VERSION 5.7 ;
  NOWIREEXTENSIONATPIN ON ;
  DIVIDERCHAR "/" ;
  BUSBITCHARS "[]" ;
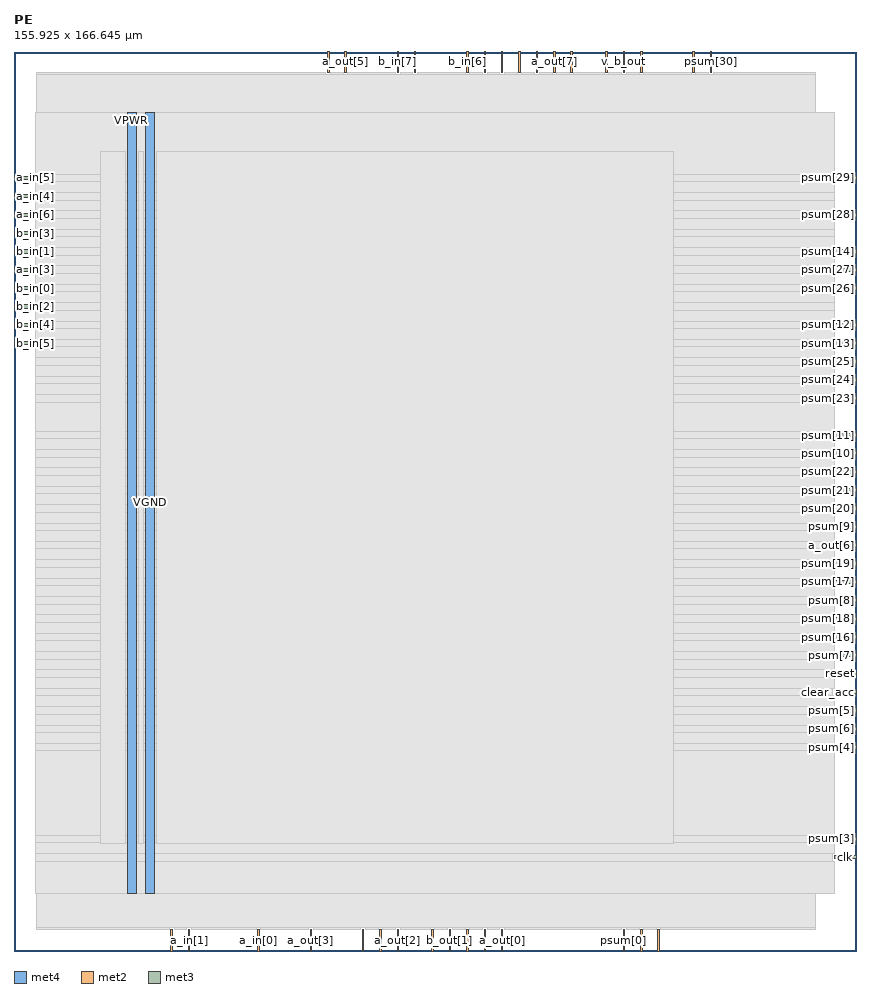
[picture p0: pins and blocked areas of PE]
MACRO PE
  CLASS BLOCK ;
  FOREIGN PE ;
  ORIGIN 0.000 0.000 ;
  SIZE 155.925 BY 166.645 ;
  PIN VGND
    DIRECTION INOUT ;
    USE GROUND ;
    PORT
      LAYER met4 ;
        RECT 24.340 10.640 25.940 155.280 ;
    END
  END VGND
  PIN VPWR
    DIRECTION INOUT ;
    USE POWER ;
    PORT
      LAYER met4 ;
        RECT 21.040 10.640 22.640 155.280 ;
    END
  END VPWR
  PIN a_in[0]
    DIRECTION INPUT ;
    USE SIGNAL ;
    ANTENNAGATEAREA 0.196500 ;
    PORT
      LAYER met2 ;
        RECT 45.170 0.000 45.450 4.000 ;
    END
  END a_in[0]
  PIN a_in[1]
    DIRECTION INPUT ;
    USE SIGNAL ;
    ANTENNAGATEAREA 0.213000 ;
    PORT
      LAYER met2 ;
        RECT 32.290 0.000 32.570 4.000 ;
    END
  END a_in[1]
  PIN a_in[2]
    DIRECTION INPUT ;
    USE SIGNAL ;
    ANTENNAGATEAREA 0.196500 ;
    PORT
      LAYER met2 ;
        RECT 29.070 0.000 29.350 4.000 ;
    END
  END a_in[2]
  PIN a_in[3]
    DIRECTION INPUT ;
    USE SIGNAL ;
    ANTENNAGATEAREA 0.196500 ;
    PORT
      LAYER met3 ;
        RECT 0.000 125.840 4.000 126.440 ;
    END
  END a_in[3]
  PIN a_in[4]
    DIRECTION INPUT ;
    USE SIGNAL ;
    ANTENNAGATEAREA 0.159000 ;
    PORT
      LAYER met3 ;
        RECT 0.000 139.440 4.000 140.040 ;
    END
  END a_in[4]
  PIN a_in[5]
    DIRECTION INPUT ;
    USE SIGNAL ;
    ANTENNAGATEAREA 0.196500 ;
    PORT
      LAYER met3 ;
        RECT 0.000 142.840 4.000 143.440 ;
    END
  END a_in[5]
  PIN a_in[6]
    DIRECTION INPUT ;
    USE SIGNAL ;
    ANTENNAGATEAREA 0.495000 ;
    PORT
      LAYER met3 ;
        RECT 0.000 136.040 4.000 136.640 ;
    END
  END a_in[6]
  PIN a_in[7]
    DIRECTION INPUT ;
    USE SIGNAL ;
    ANTENNAGATEAREA 0.196500 ;
    PORT
      LAYER met2 ;
        RECT 74.150 162.645 74.430 166.645 ;
    END
  END a_in[7]
  PIN a_out[0]
    DIRECTION OUTPUT ;
    USE SIGNAL ;
    ANTENNADIFFAREA 0.445500 ;
    PORT
      LAYER met2 ;
        RECT 90.250 0.000 90.530 4.000 ;
    END
  END a_out[0]
  PIN a_out[1]
    DIRECTION OUTPUT ;
    USE SIGNAL ;
    ANTENNADIFFAREA 0.445500 ;
    PORT
      LAYER met2 ;
        RECT 83.810 0.000 84.090 4.000 ;
    END
  END a_out[1]
  PIN a_out[2]
    DIRECTION OUTPUT ;
    USE SIGNAL ;
    ANTENNADIFFAREA 0.445500 ;
    PORT
      LAYER met2 ;
        RECT 70.930 0.000 71.210 4.000 ;
    END
  END a_out[2]
  PIN a_out[3]
    DIRECTION OUTPUT ;
    USE SIGNAL ;
    ANTENNADIFFAREA 0.445500 ;
    PORT
      LAYER met2 ;
        RECT 54.830 0.000 55.110 4.000 ;
    END
  END a_out[3]
  PIN a_out[4]
    DIRECTION OUTPUT ;
    USE SIGNAL ;
    ANTENNADIFFAREA 0.445500 ;
    PORT
      LAYER met2 ;
        RECT 58.050 162.645 58.330 166.645 ;
    END
  END a_out[4]
  PIN a_out[5]
    DIRECTION OUTPUT ;
    USE SIGNAL ;
    ANTENNADIFFAREA 0.445500 ;
    PORT
      LAYER met2 ;
        RECT 61.270 162.645 61.550 166.645 ;
    END
  END a_out[5]
  PIN a_out[6]
    DIRECTION OUTPUT ;
    USE SIGNAL ;
    ANTENNADIFFAREA 0.445500 ;
    PORT
      LAYER met3 ;
        RECT 151.925 74.840 155.925 75.440 ;
    END
  END a_out[6]
  PIN a_out[7]
    DIRECTION OUTPUT ;
    USE SIGNAL ;
    ANTENNADIFFAREA 0.445500 ;
    PORT
      LAYER met2 ;
        RECT 99.910 162.645 100.190 166.645 ;
    END
  END a_out[7]
  PIN b_in[0]
    DIRECTION INPUT ;
    USE SIGNAL ;
    ANTENNAGATEAREA 0.196500 ;
    PORT
      LAYER met3 ;
        RECT 0.000 122.440 4.000 123.040 ;
    END
  END b_in[0]
  PIN b_in[1]
    DIRECTION INPUT ;
    USE SIGNAL ;
    ANTENNAGATEAREA 0.742500 ;
    PORT
      LAYER met3 ;
        RECT 0.000 129.240 4.000 129.840 ;
    END
  END b_in[1]
  PIN b_in[2]
    DIRECTION INPUT ;
    USE SIGNAL ;
    ANTENNAGATEAREA 0.196500 ;
    PORT
      LAYER met3 ;
        RECT 0.000 119.040 4.000 119.640 ;
    END
  END b_in[2]
  PIN b_in[3]
    DIRECTION INPUT ;
    USE SIGNAL ;
    ANTENNAGATEAREA 0.196500 ;
    PORT
      LAYER met3 ;
        RECT 0.000 132.640 4.000 133.240 ;
    END
  END b_in[3]
  PIN b_in[4]
    DIRECTION INPUT ;
    USE SIGNAL ;
    ANTENNAGATEAREA 0.196500 ;
    PORT
      LAYER met3 ;
        RECT 0.000 115.640 4.000 116.240 ;
    END
  END b_in[4]
  PIN b_in[5]
    DIRECTION INPUT ;
    USE SIGNAL ;
    ANTENNAGATEAREA 0.196500 ;
    PORT
      LAYER met3 ;
        RECT 0.000 112.240 4.000 112.840 ;
    END
  END b_in[5]
  PIN b_in[6]
    DIRECTION INPUT ;
    USE SIGNAL ;
    ANTENNAGATEAREA 0.196500 ;
    PORT
      LAYER met2 ;
        RECT 83.810 162.645 84.090 166.645 ;
    END
  END b_in[6]
  PIN b_in[7]
    DIRECTION INPUT ;
    USE SIGNAL ;
    ANTENNAGATEAREA 0.196500 ;
    PORT
      LAYER met2 ;
        RECT 70.930 162.645 71.210 166.645 ;
    END
  END b_in[7]
  PIN b_out[0]
    DIRECTION OUTPUT ;
    USE SIGNAL ;
    ANTENNADIFFAREA 0.445500 ;
    PORT
      LAYER met2 ;
        RECT 87.030 0.000 87.310 4.000 ;
    END
  END b_out[0]
  PIN b_out[1]
    DIRECTION OUTPUT ;
    USE SIGNAL ;
    ANTENNADIFFAREA 0.445500 ;
    PORT
      LAYER met2 ;
        RECT 80.590 0.000 80.870 4.000 ;
    END
  END b_out[1]
  PIN b_out[2]
    DIRECTION OUTPUT ;
    USE SIGNAL ;
    ANTENNADIFFAREA 0.445500 ;
    PORT
      LAYER met2 ;
        RECT 77.370 0.000 77.650 4.000 ;
    END
  END b_out[2]
  PIN b_out[3]
    DIRECTION OUTPUT ;
    USE SIGNAL ;
    ANTENNADIFFAREA 0.445500 ;
    PORT
      LAYER met2 ;
        RECT 64.490 0.000 64.770 4.000 ;
    END
  END b_out[3]
  PIN b_out[4]
    DIRECTION OUTPUT ;
    USE SIGNAL ;
    ANTENNADIFFAREA 0.445500 ;
    PORT
      LAYER met2 ;
        RECT 67.710 0.000 67.990 4.000 ;
    END
  END b_out[4]
  PIN b_out[5]
    DIRECTION OUTPUT ;
    USE SIGNAL ;
    ANTENNADIFFAREA 0.445500 ;
    PORT
      LAYER met2 ;
        RECT 90.250 162.645 90.530 166.645 ;
    END
  END b_out[5]
  PIN b_out[6]
    DIRECTION OUTPUT ;
    USE SIGNAL ;
    ANTENNADIFFAREA 0.445500 ;
    PORT
      LAYER met2 ;
        RECT 87.030 162.645 87.310 166.645 ;
    END
  END b_out[6]
  PIN b_out[7]
    DIRECTION OUTPUT ;
    USE SIGNAL ;
    ANTENNADIFFAREA 0.445500 ;
    PORT
      LAYER met2 ;
        RECT 96.690 162.645 96.970 166.645 ;
    END
  END b_out[7]
  PIN clear_acc
    DIRECTION INPUT ;
    USE SIGNAL ;
    ANTENNAGATEAREA 0.126000 ;
    PORT
      LAYER met3 ;
        RECT 151.925 47.640 155.925 48.240 ;
    END
  END clear_acc
  PIN clk
    DIRECTION INPUT ;
    USE SIGNAL ;
    ANTENNAGATEAREA 0.852000 ;
    PORT
      LAYER met3 ;
        RECT 151.925 17.040 155.925 17.640 ;
    END
  END clk
  PIN psum[0]
    DIRECTION OUTPUT ;
    USE SIGNAL ;
    ANTENNADIFFAREA 0.445500 ;
    PORT
      LAYER met2 ;
        RECT 112.790 0.000 113.070 4.000 ;
    END
  END psum[0]
  PIN psum[10]
    DIRECTION OUTPUT ;
    USE SIGNAL ;
    ANTENNADIFFAREA 0.445500 ;
    PORT
      LAYER met3 ;
        RECT 151.925 91.840 155.925 92.440 ;
    END
  END psum[10]
  PIN psum[11]
    DIRECTION OUTPUT ;
    USE SIGNAL ;
    ANTENNADIFFAREA 0.445500 ;
    PORT
      LAYER met3 ;
        RECT 151.925 95.240 155.925 95.840 ;
    END
  END psum[11]
  PIN psum[12]
    DIRECTION OUTPUT ;
    USE SIGNAL ;
    ANTENNADIFFAREA 0.445500 ;
    PORT
      LAYER met3 ;
        RECT 151.925 115.640 155.925 116.240 ;
    END
  END psum[12]
  PIN psum[13]
    DIRECTION OUTPUT ;
    USE SIGNAL ;
    ANTENNADIFFAREA 0.445500 ;
    PORT
      LAYER met3 ;
        RECT 151.925 112.240 155.925 112.840 ;
    END
  END psum[13]
  PIN psum[14]
    DIRECTION OUTPUT ;
    USE SIGNAL ;
    ANTENNADIFFAREA 0.445500 ;
    PORT
      LAYER met3 ;
        RECT 151.925 129.240 155.925 129.840 ;
    END
  END psum[14]
  PIN psum[15]
    DIRECTION OUTPUT ;
    USE SIGNAL ;
    ANTENNADIFFAREA 0.445500 ;
    PORT
      LAYER met2 ;
        RECT 116.010 162.645 116.290 166.645 ;
    END
  END psum[15]
  PIN psum[16]
    DIRECTION OUTPUT ;
    USE SIGNAL ;
    ANTENNADIFFAREA 0.445500 ;
    PORT
      LAYER met3 ;
        RECT 151.925 57.840 155.925 58.440 ;
    END
  END psum[16]
  PIN psum[17]
    DIRECTION OUTPUT ;
    USE SIGNAL ;
    ANTENNADIFFAREA 0.445500 ;
    PORT
      LAYER met3 ;
        RECT 151.925 68.040 155.925 68.640 ;
    END
  END psum[17]
  PIN psum[18]
    DIRECTION OUTPUT ;
    USE SIGNAL ;
    ANTENNADIFFAREA 0.445500 ;
    PORT
      LAYER met3 ;
        RECT 151.925 61.240 155.925 61.840 ;
    END
  END psum[18]
  PIN psum[19]
    DIRECTION OUTPUT ;
    USE SIGNAL ;
    ANTENNADIFFAREA 0.445500 ;
    PORT
      LAYER met3 ;
        RECT 151.925 71.440 155.925 72.040 ;
    END
  END psum[19]
  PIN psum[1]
    DIRECTION OUTPUT ;
    USE SIGNAL ;
    ANTENNADIFFAREA 0.445500 ;
    PORT
      LAYER met2 ;
        RECT 116.010 0.000 116.290 4.000 ;
    END
  END psum[1]
  PIN psum[20]
    DIRECTION OUTPUT ;
    USE SIGNAL ;
    ANTENNADIFFAREA 0.445500 ;
    PORT
      LAYER met3 ;
        RECT 151.925 81.640 155.925 82.240 ;
    END
  END psum[20]
  PIN psum[21]
    DIRECTION OUTPUT ;
    USE SIGNAL ;
    ANTENNADIFFAREA 0.445500 ;
    PORT
      LAYER met3 ;
        RECT 151.925 85.040 155.925 85.640 ;
    END
  END psum[21]
  PIN psum[22]
    DIRECTION OUTPUT ;
    USE SIGNAL ;
    ANTENNADIFFAREA 0.445500 ;
    PORT
      LAYER met3 ;
        RECT 151.925 88.440 155.925 89.040 ;
    END
  END psum[22]
  PIN psum[23]
    DIRECTION OUTPUT ;
    USE SIGNAL ;
    ANTENNADIFFAREA 0.445500 ;
    PORT
      LAYER met3 ;
        RECT 151.925 102.040 155.925 102.640 ;
    END
  END psum[23]
  PIN psum[24]
    DIRECTION OUTPUT ;
    USE SIGNAL ;
    ANTENNADIFFAREA 0.445500 ;
    PORT
      LAYER met3 ;
        RECT 151.925 105.440 155.925 106.040 ;
    END
  END psum[24]
  PIN psum[25]
    DIRECTION OUTPUT ;
    USE SIGNAL ;
    ANTENNADIFFAREA 0.445500 ;
    PORT
      LAYER met3 ;
        RECT 151.925 108.840 155.925 109.440 ;
    END
  END psum[25]
  PIN psum[26]
    DIRECTION OUTPUT ;
    USE SIGNAL ;
    ANTENNADIFFAREA 0.445500 ;
    PORT
      LAYER met3 ;
        RECT 151.925 122.440 155.925 123.040 ;
    END
  END psum[26]
  PIN psum[27]
    DIRECTION OUTPUT ;
    USE SIGNAL ;
    ANTENNADIFFAREA 0.445500 ;
    PORT
      LAYER met3 ;
        RECT 151.925 125.840 155.925 126.440 ;
    END
  END psum[27]
  PIN psum[28]
    DIRECTION OUTPUT ;
    USE SIGNAL ;
    ANTENNADIFFAREA 0.445500 ;
    PORT
      LAYER met3 ;
        RECT 151.925 136.040 155.925 136.640 ;
    END
  END psum[28]
  PIN psum[29]
    DIRECTION OUTPUT ;
    USE SIGNAL ;
    ANTENNADIFFAREA 0.445500 ;
    PORT
      LAYER met3 ;
        RECT 151.925 142.840 155.925 143.440 ;
    END
  END psum[29]
  PIN psum[2]
    DIRECTION OUTPUT ;
    USE SIGNAL ;
    ANTENNADIFFAREA 0.445500 ;
    PORT
      LAYER met2 ;
        RECT 119.230 0.000 119.510 4.000 ;
    END
  END psum[2]
  PIN psum[30]
    DIRECTION OUTPUT ;
    USE SIGNAL ;
    ANTENNADIFFAREA 0.445500 ;
    PORT
      LAYER met2 ;
        RECT 128.890 162.645 129.170 166.645 ;
    END
  END psum[30]
  PIN psum[31]
    DIRECTION OUTPUT ;
    USE SIGNAL ;
    ANTENNADIFFAREA 0.445500 ;
    PORT
      LAYER met2 ;
        RECT 125.670 162.645 125.950 166.645 ;
    END
  END psum[31]
  PIN psum[3]
    DIRECTION OUTPUT ;
    USE SIGNAL ;
    ANTENNADIFFAREA 0.445500 ;
    PORT
      LAYER met3 ;
        RECT 151.925 20.440 155.925 21.040 ;
    END
  END psum[3]
  PIN psum[4]
    DIRECTION OUTPUT ;
    USE SIGNAL ;
    ANTENNADIFFAREA 0.445500 ;
    PORT
      LAYER met3 ;
        RECT 151.925 37.440 155.925 38.040 ;
    END
  END psum[4]
  PIN psum[5]
    DIRECTION OUTPUT ;
    USE SIGNAL ;
    ANTENNADIFFAREA 0.445500 ;
    PORT
      LAYER met3 ;
        RECT 151.925 44.240 155.925 44.840 ;
    END
  END psum[5]
  PIN psum[6]
    DIRECTION OUTPUT ;
    USE SIGNAL ;
    ANTENNADIFFAREA 0.445500 ;
    PORT
      LAYER met3 ;
        RECT 151.925 40.840 155.925 41.440 ;
    END
  END psum[6]
  PIN psum[7]
    DIRECTION OUTPUT ;
    USE SIGNAL ;
    ANTENNADIFFAREA 0.445500 ;
    PORT
      LAYER met3 ;
        RECT 151.925 54.440 155.925 55.040 ;
    END
  END psum[7]
  PIN psum[8]
    DIRECTION OUTPUT ;
    USE SIGNAL ;
    ANTENNADIFFAREA 0.445500 ;
    PORT
      LAYER met3 ;
        RECT 151.925 64.640 155.925 65.240 ;
    END
  END psum[8]
  PIN psum[9]
    DIRECTION OUTPUT ;
    USE SIGNAL ;
    ANTENNADIFFAREA 0.445500 ;
    PORT
      LAYER met3 ;
        RECT 151.925 78.240 155.925 78.840 ;
    END
  END psum[9]
  PIN reset
    DIRECTION INPUT ;
    USE SIGNAL ;
    ANTENNAGATEAREA 0.126000 ;
    PORT
      LAYER met3 ;
        RECT 151.925 51.040 155.925 51.640 ;
    END
  END reset
  PIN v_a_in
    DIRECTION INPUT ;
    USE SIGNAL ;
    ANTENNAGATEAREA 0.126000 ;
    PORT
      LAYER met2 ;
        RECT 93.470 162.645 93.750 166.645 ;
    END
  END v_a_in
  PIN v_a_out
    DIRECTION OUTPUT ;
    USE SIGNAL ;
    ANTENNADIFFAREA 0.445500 ;
    PORT
      LAYER met2 ;
        RECT 109.570 162.645 109.850 166.645 ;
    END
  END v_a_out
  PIN v_b_in
    DIRECTION INPUT ;
    USE SIGNAL ;
    ANTENNAGATEAREA 0.126000 ;
    PORT
      LAYER met2 ;
        RECT 103.130 162.645 103.410 166.645 ;
    END
  END v_b_in
  PIN v_b_out
    DIRECTION OUTPUT ;
    USE SIGNAL ;
    ANTENNADIFFAREA 0.445500 ;
    PORT
      LAYER met2 ;
        RECT 112.790 162.645 113.070 166.645 ;
    END
  END v_b_out
  OBS
      LAYER nwell ;
        RECT 5.330 10.795 150.150 155.230 ;
      LAYER li1 ;
        RECT 5.520 10.795 149.960 155.125 ;
      LAYER met1 ;
        RECT 4.210 10.640 150.260 155.280 ;
      LAYER met2 ;
        RECT 4.230 162.365 57.770 162.645 ;
        RECT 58.610 162.365 60.990 162.645 ;
        RECT 61.830 162.365 70.650 162.645 ;
        RECT 71.490 162.365 73.870 162.645 ;
        RECT 74.710 162.365 83.530 162.645 ;
        RECT 84.370 162.365 86.750 162.645 ;
        RECT 87.590 162.365 89.970 162.645 ;
        RECT 90.810 162.365 93.190 162.645 ;
        RECT 94.030 162.365 96.410 162.645 ;
        RECT 97.250 162.365 99.630 162.645 ;
        RECT 100.470 162.365 102.850 162.645 ;
        RECT 103.690 162.365 109.290 162.645 ;
        RECT 110.130 162.365 112.510 162.645 ;
        RECT 113.350 162.365 115.730 162.645 ;
        RECT 116.570 162.365 125.390 162.645 ;
        RECT 126.230 162.365 128.610 162.645 ;
        RECT 129.450 162.365 148.490 162.645 ;
        RECT 4.230 4.280 148.490 162.365 ;
        RECT 4.230 4.000 28.790 4.280 ;
        RECT 29.630 4.000 32.010 4.280 ;
        RECT 32.850 4.000 44.890 4.280 ;
        RECT 45.730 4.000 54.550 4.280 ;
        RECT 55.390 4.000 64.210 4.280 ;
        RECT 65.050 4.000 67.430 4.280 ;
        RECT 68.270 4.000 70.650 4.280 ;
        RECT 71.490 4.000 77.090 4.280 ;
        RECT 77.930 4.000 80.310 4.280 ;
        RECT 81.150 4.000 83.530 4.280 ;
        RECT 84.370 4.000 86.750 4.280 ;
        RECT 87.590 4.000 89.970 4.280 ;
        RECT 90.810 4.000 112.510 4.280 ;
        RECT 113.350 4.000 115.730 4.280 ;
        RECT 116.570 4.000 118.950 4.280 ;
        RECT 119.790 4.000 148.490 4.280 ;
      LAYER met3 ;
        RECT 3.990 143.840 151.925 155.205 ;
        RECT 4.400 142.440 151.525 143.840 ;
        RECT 3.990 140.440 151.925 142.440 ;
        RECT 4.400 139.040 151.925 140.440 ;
        RECT 3.990 137.040 151.925 139.040 ;
        RECT 4.400 135.640 151.525 137.040 ;
        RECT 3.990 133.640 151.925 135.640 ;
        RECT 4.400 132.240 151.925 133.640 ;
        RECT 3.990 130.240 151.925 132.240 ;
        RECT 4.400 128.840 151.525 130.240 ;
        RECT 3.990 126.840 151.925 128.840 ;
        RECT 4.400 125.440 151.525 126.840 ;
        RECT 3.990 123.440 151.925 125.440 ;
        RECT 4.400 122.040 151.525 123.440 ;
        RECT 3.990 120.040 151.925 122.040 ;
        RECT 4.400 118.640 151.925 120.040 ;
        RECT 3.990 116.640 151.925 118.640 ;
        RECT 4.400 115.240 151.525 116.640 ;
        RECT 3.990 113.240 151.925 115.240 ;
        RECT 4.400 111.840 151.525 113.240 ;
        RECT 3.990 109.840 151.925 111.840 ;
        RECT 3.990 108.440 151.525 109.840 ;
        RECT 3.990 106.440 151.925 108.440 ;
        RECT 3.990 105.040 151.525 106.440 ;
        RECT 3.990 103.040 151.925 105.040 ;
        RECT 3.990 101.640 151.525 103.040 ;
        RECT 3.990 96.240 151.925 101.640 ;
        RECT 3.990 94.840 151.525 96.240 ;
        RECT 3.990 92.840 151.925 94.840 ;
        RECT 3.990 91.440 151.525 92.840 ;
        RECT 3.990 89.440 151.925 91.440 ;
        RECT 3.990 88.040 151.525 89.440 ;
        RECT 3.990 86.040 151.925 88.040 ;
        RECT 3.990 84.640 151.525 86.040 ;
        RECT 3.990 82.640 151.925 84.640 ;
        RECT 3.990 81.240 151.525 82.640 ;
        RECT 3.990 79.240 151.925 81.240 ;
        RECT 3.990 77.840 151.525 79.240 ;
        RECT 3.990 75.840 151.925 77.840 ;
        RECT 3.990 74.440 151.525 75.840 ;
        RECT 3.990 72.440 151.925 74.440 ;
        RECT 3.990 71.040 151.525 72.440 ;
        RECT 3.990 69.040 151.925 71.040 ;
        RECT 3.990 67.640 151.525 69.040 ;
        RECT 3.990 65.640 151.925 67.640 ;
        RECT 3.990 64.240 151.525 65.640 ;
        RECT 3.990 62.240 151.925 64.240 ;
        RECT 3.990 60.840 151.525 62.240 ;
        RECT 3.990 58.840 151.925 60.840 ;
        RECT 3.990 57.440 151.525 58.840 ;
        RECT 3.990 55.440 151.925 57.440 ;
        RECT 3.990 54.040 151.525 55.440 ;
        RECT 3.990 52.040 151.925 54.040 ;
        RECT 3.990 50.640 151.525 52.040 ;
        RECT 3.990 48.640 151.925 50.640 ;
        RECT 3.990 47.240 151.525 48.640 ;
        RECT 3.990 45.240 151.925 47.240 ;
        RECT 3.990 43.840 151.525 45.240 ;
        RECT 3.990 41.840 151.925 43.840 ;
        RECT 3.990 40.440 151.525 41.840 ;
        RECT 3.990 38.440 151.925 40.440 ;
        RECT 3.990 37.040 151.525 38.440 ;
        RECT 3.990 21.440 151.925 37.040 ;
        RECT 3.990 20.040 151.525 21.440 ;
        RECT 3.990 18.040 151.925 20.040 ;
        RECT 3.990 16.640 151.525 18.040 ;
        RECT 3.990 10.715 151.925 16.640 ;
      LAYER met4 ;
        RECT 15.935 19.895 20.640 148.065 ;
        RECT 23.040 19.895 23.940 148.065 ;
        RECT 26.340 19.895 122.065 148.065 ;
  END
END PE
END LIBRARY

